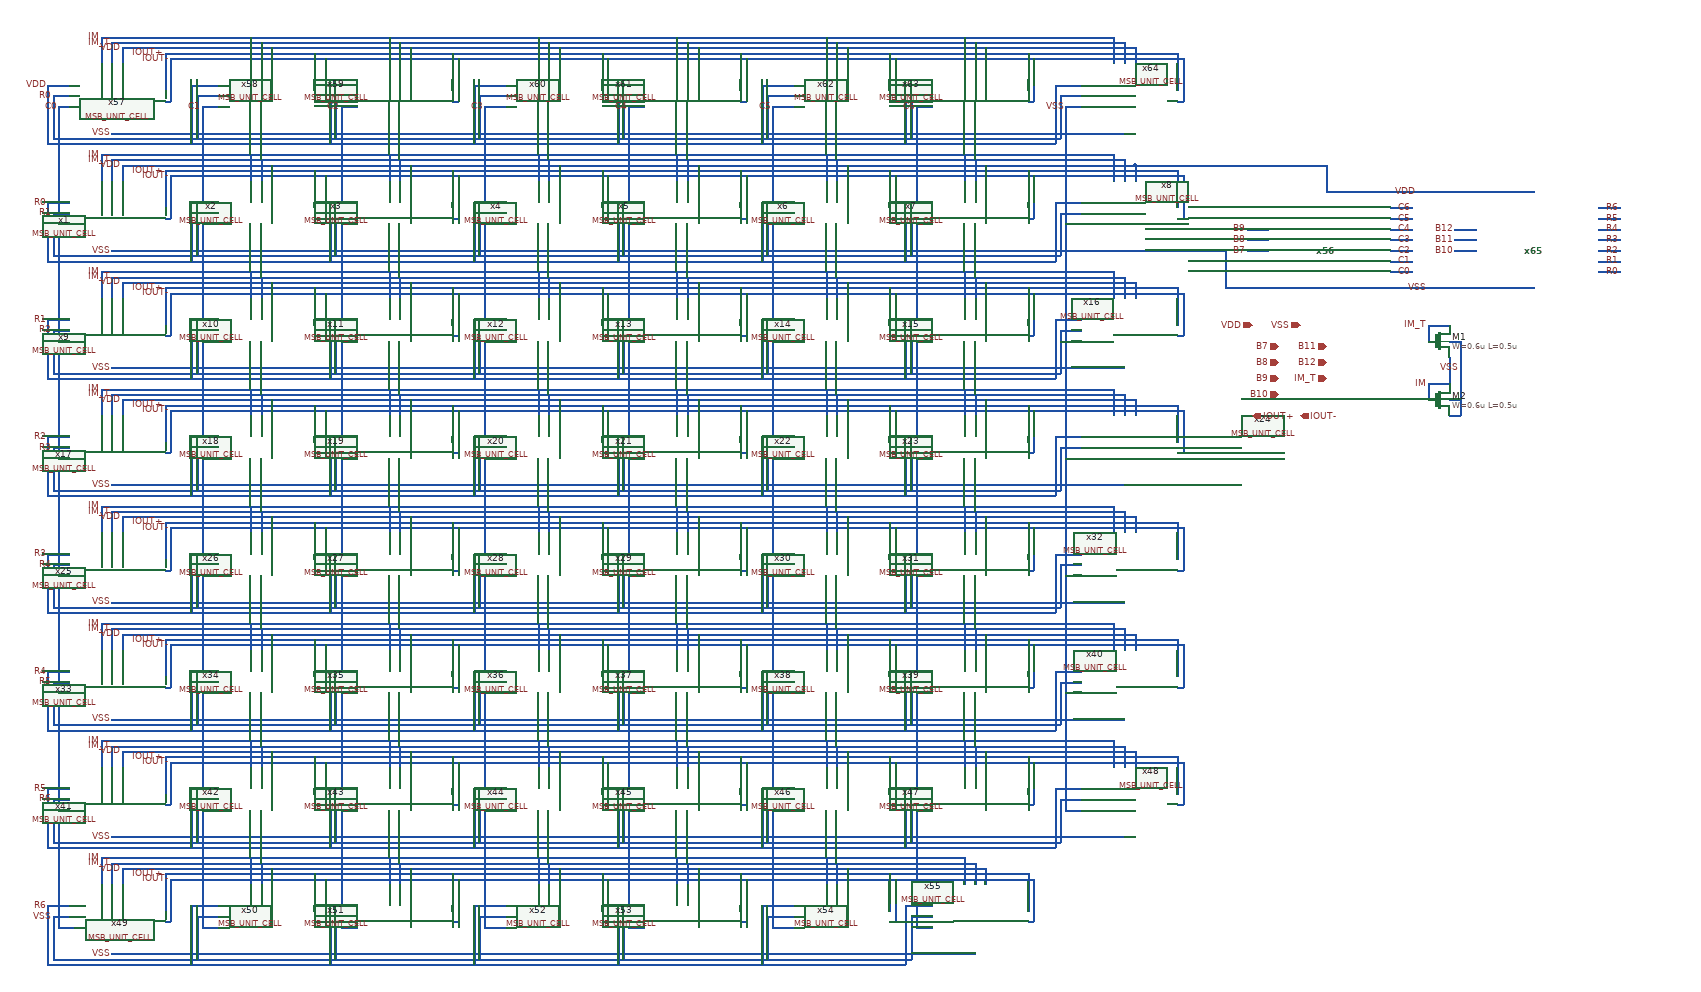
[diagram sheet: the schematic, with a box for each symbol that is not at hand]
v {xschem version=3.1.0 file_version=1.2
}
G {}
K {}
V {}
S {}
E {}
N 200 -1780 200 -1730 {
lab=IM}
N 200 -1780 2100 -1780 {
lab=IM}
N 2100 -1780 2100 -1730 {
lab=IM}
N 2120 -1770 2120 -1730 {
lab=IM_T}
N 2110 -1770 2120 -1770 {
lab=IM_T}
N 220 -1770 2110 -1770 {
lab=IM_T}
N 220 -1770 220 -1730 {
lab=IM_T}
N 240 -1760 240 -1730 {
lab=VDD}
N 240 -1760 2140 -1760 {
lab=VDD}
N 2140 -1760 2140 -1730 {
lab=VDD}
N 2220 -1750 2220 -1680 {
lab=IOUT+}
N 320 -1750 2220 -1750 {
lab=IOUT+}
N 320 -1750 320 -1680 {
lab=IOUT+}
N 320 -1660 330 -1660 {
lab=IOUT-}
N 330 -1740 330 -1660 {
lab=IOUT-}
N 330 -1740 2230 -1740 {
lab=IOUT-}
N 2230 -1740 2230 -1660 {
lab=IOUT-}
N 2220 -1660 2230 -1660 {
lab=IOUT-}
N 220 -1600 2120 -1600 {
lab=VSS}
N 480 -1780 480 -1730 {
lab=IM}
N 500 -1770 500 -1730 {
lab=IM_T}
N 520 -1760 520 -1730 {
lab=VDD}
N 600 -1750 600 -1680 {
lab=IOUT+}
N 600 -1660 620 -1660 {
lab=IOUT-}
N 620 -1740 620 -1660 {
lab=IOUT-}
N 740 -1780 740 -1730 {
lab=IM}
N 760 -1770 760 -1730 {
lab=IM_T}
N 780 -1760 780 -1730 {
lab=VDD}
N 860 -1750 860 -1680 {
lab=IOUT+}
N 870 -1740 870 -1660 {
lab=IOUT-}
N 860 -1660 870 -1660 {
lab=IOUT-}
N 1020 -1780 1020 -1730 {
lab=IM}
N 1040 -1770 1040 -1730 {
lab=IM_T}
N 1060 -1760 1060 -1730 {
lab=VDD}
N 1140 -1750 1140 -1680 {
lab=IOUT+}
N 1140 -1660 1150 -1660 {
lab=IOUT-}
N 1150 -1740 1150 -1660 {
lab=IOUT-}
N 1280 -1780 1280 -1730 {
lab=IM}
N 1300 -1770 1300 -1730 {
lab=IM_T}
N 1320 -1760 1320 -1730 {
lab=VDD}
N 1400 -1750 1400 -1680 {
lab=IOUT+}
N 1410 -1740 1410 -1660 {
lab=IOUT-}
N 1400 -1660 1410 -1660 {
lab=IOUT-}
N 1560 -1780 1560 -1730 {
lab=IM}
N 1580 -1770 1580 -1730 {
lab=IM_T}
N 1600 -1760 1600 -1730 {
lab=VDD}
N 1680 -1750 1680 -1680 {
lab=IOUT+}
N 1690 -1740 1690 -1660 {
lab=IOUT-}
N 1680 -1660 1690 -1660 {
lab=IOUT-}
N 1820 -1780 1820 -1730 {
lab=IM}
N 1840 -1770 1840 -1730 {
lab=IM_T}
N 1860 -1760 1860 -1730 {
lab=VDD}
N 1940 -1750 1940 -1680 {
lab=IOUT+}
N 1940 -1660 1950 -1660 {
lab=IOUT-}
N 1950 -1740 1950 -1660 {
lab=IOUT-}
N 110 -1670 140 -1670 {
lab=R0}
N 110 -1670 110 -1590 {
lab=R0}
N 110 -1590 2000 -1590 {
lab=R0}
N 2000 -1670 2000 -1590 {
lab=R0}
N 2000 -1670 2040 -1670 {
lab=R0}
N 1990 -1690 2040 -1690 {
lab=VDD}
N 1990 -1690 1990 -1580 {
lab=VDD}
N 100 -1580 1990 -1580 {
lab=VDD}
N 100 -1690 100 -1580 {
lab=VDD}
N 100 -1690 140 -1690 {
lab=VDD}
N 370 -1690 420 -1690 {
lab=VDD}
N 370 -1690 370 -1580 {
lab=VDD}
N 380 -1670 380 -1590 {
lab=R0}
N 380 -1670 420 -1670 {
lab=R0}
N 630 -1690 680 -1690 {
lab=VDD}
N 630 -1690 630 -1580 {
lab=VDD}
N 640 -1670 680 -1670 {
lab=R0}
N 640 -1670 640 -1590 {
lab=R0}
N 900 -1690 960 -1690 {
lab=VDD}
N 900 -1690 900 -1580 {
lab=VDD}
N 910 -1670 960 -1670 {
lab=R0}
N 910 -1670 910 -1590 {
lab=R0}
N 1170 -1690 1220 -1690 {
lab=VDD}
N 1170 -1690 1170 -1580 {
lab=VDD}
N 1180 -1670 1220 -1670 {
lab=R0}
N 1180 -1670 1180 -1590 {
lab=R0}
N 1440 -1690 1500 -1690 {
lab=VDD}
N 1440 -1690 1440 -1580 {
lab=VDD}
N 1450 -1670 1500 -1670 {
lab=R0}
N 1450 -1670 1450 -1590 {
lab=R0}
N 1710 -1690 1760 -1690 {
lab=VDD}
N 1710 -1690 1710 -1580 {
lab=VDD}
N 1720 -1670 1760 -1670 {
lab=R0}
N 1720 -1670 1720 -1590 {
lab=R0}
N 200 -1560 200 -1510 {
lab=IM}
N 200 -1560 2100 -1560 {
lab=IM}
N 2100 -1560 2100 -1510 {
lab=IM}
N 2120 -1550 2120 -1510 {
lab=IM_T}
N 2110 -1550 2120 -1550 {
lab=IM_T}
N 220 -1550 2110 -1550 {
lab=IM_T}
N 220 -1550 220 -1510 {
lab=IM_T}
N 240 -1540 240 -1510 {
lab=VDD}
N 240 -1540 2140 -1540 {
lab=VDD}
N 2140 -1540 2140 -1510 {
lab=VDD}
N 2220 -1530 2220 -1460 {
lab=IOUT+}
N 320 -1530 2220 -1530 {
lab=IOUT+}
N 320 -1530 320 -1460 {
lab=IOUT+}
N 320 -1440 330 -1440 {
lab=IOUT-}
N 330 -1520 330 -1440 {
lab=IOUT-}
N 330 -1520 2230 -1520 {
lab=IOUT-}
N 2230 -1520 2230 -1440 {
lab=IOUT-}
N 2220 -1440 2230 -1440 {
lab=IOUT-}
N 220 -1380 2120 -1380 {
lab=VSS}
N 480 -1560 480 -1510 {
lab=IM}
N 500 -1550 500 -1510 {
lab=IM_T}
N 520 -1540 520 -1510 {
lab=VDD}
N 600 -1530 600 -1460 {
lab=IOUT+}
N 600 -1440 620 -1440 {
lab=IOUT-}
N 620 -1520 620 -1440 {
lab=IOUT-}
N 740 -1560 740 -1510 {
lab=IM}
N 760 -1550 760 -1510 {
lab=IM_T}
N 780 -1540 780 -1510 {
lab=VDD}
N 860 -1530 860 -1460 {
lab=IOUT+}
N 870 -1520 870 -1440 {
lab=IOUT-}
N 860 -1440 870 -1440 {
lab=IOUT-}
N 1020 -1560 1020 -1510 {
lab=IM}
N 1040 -1550 1040 -1510 {
lab=IM_T}
N 1060 -1540 1060 -1510 {
lab=VDD}
N 1140 -1530 1140 -1460 {
lab=IOUT+}
N 1140 -1440 1150 -1440 {
lab=IOUT-}
N 1150 -1520 1150 -1440 {
lab=IOUT-}
N 1280 -1560 1280 -1510 {
lab=IM}
N 1300 -1550 1300 -1510 {
lab=IM_T}
N 1320 -1540 1320 -1510 {
lab=VDD}
N 1400 -1530 1400 -1460 {
lab=IOUT+}
N 1410 -1520 1410 -1440 {
lab=IOUT-}
N 1400 -1440 1410 -1440 {
lab=IOUT-}
N 1560 -1560 1560 -1510 {
lab=IM}
N 1580 -1550 1580 -1510 {
lab=IM_T}
N 1600 -1540 1600 -1510 {
lab=VDD}
N 1680 -1530 1680 -1460 {
lab=IOUT+}
N 1690 -1520 1690 -1440 {
lab=IOUT-}
N 1680 -1440 1690 -1440 {
lab=IOUT-}
N 1820 -1560 1820 -1510 {
lab=IM}
N 1840 -1550 1840 -1510 {
lab=IM_T}
N 1860 -1540 1860 -1510 {
lab=VDD}
N 1940 -1530 1940 -1460 {
lab=IOUT+}
N 1940 -1440 1950 -1440 {
lab=IOUT-}
N 1950 -1520 1950 -1440 {
lab=IOUT-}
N 110 -1450 140 -1450 {
lab=R1}
N 110 -1450 110 -1370 {
lab=R1}
N 110 -1370 2000 -1370 {
lab=R1}
N 2000 -1450 2000 -1370 {
lab=R1}
N 2000 -1450 2040 -1450 {
lab=R1}
N 1990 -1470 2040 -1470 {
lab=R0}
N 1990 -1470 1990 -1360 {
lab=R0}
N 100 -1360 1990 -1360 {
lab=R0}
N 100 -1470 100 -1360 {
lab=R0}
N 100 -1470 140 -1470 {
lab=R0}
N 370 -1470 420 -1470 {
lab=R0}
N 370 -1470 370 -1360 {
lab=R0}
N 380 -1450 380 -1370 {
lab=R1}
N 380 -1450 420 -1450 {
lab=R1}
N 630 -1470 680 -1470 {
lab=R0}
N 630 -1470 630 -1360 {
lab=R0}
N 640 -1450 680 -1450 {
lab=R1}
N 640 -1450 640 -1370 {
lab=R1}
N 900 -1470 960 -1470 {
lab=R0}
N 900 -1470 900 -1360 {
lab=R0}
N 910 -1450 960 -1450 {
lab=R1}
N 910 -1450 910 -1370 {
lab=R1}
N 1170 -1470 1220 -1470 {
lab=R0}
N 1170 -1470 1170 -1360 {
lab=R0}
N 1180 -1450 1220 -1450 {
lab=R1}
N 1180 -1450 1180 -1370 {
lab=R1}
N 1440 -1470 1500 -1470 {
lab=R0}
N 1440 -1470 1440 -1360 {
lab=R0}
N 1450 -1450 1500 -1450 {
lab=R1}
N 1450 -1450 1450 -1370 {
lab=R1}
N 1710 -1470 1760 -1470 {
lab=R0}
N 1710 -1470 1710 -1360 {
lab=R0}
N 1720 -1450 1760 -1450 {
lab=R1}
N 1720 -1450 1720 -1370 {
lab=R1}
N 200 -1340 200 -1290 {
lab=IM}
N 200 -1340 2100 -1340 {
lab=IM}
N 2100 -1340 2100 -1290 {
lab=IM}
N 2120 -1330 2120 -1290 {
lab=IM_T}
N 2110 -1330 2120 -1330 {
lab=IM_T}
N 220 -1330 2110 -1330 {
lab=IM_T}
N 220 -1330 220 -1290 {
lab=IM_T}
N 240 -1320 240 -1290 {
lab=VDD}
N 240 -1320 2140 -1320 {
lab=VDD}
N 2140 -1320 2140 -1290 {
lab=VDD}
N 2220 -1310 2220 -1240 {
lab=IOUT+}
N 320 -1310 2220 -1310 {
lab=IOUT+}
N 320 -1310 320 -1240 {
lab=IOUT+}
N 320 -1220 330 -1220 {
lab=IOUT-}
N 330 -1300 330 -1220 {
lab=IOUT-}
N 330 -1300 2230 -1300 {
lab=IOUT-}
N 2230 -1300 2230 -1220 {
lab=IOUT-}
N 2220 -1220 2230 -1220 {
lab=IOUT-}
N 220 -1160 2120 -1160 {
lab=VSS}
N 480 -1340 480 -1290 {
lab=IM}
N 500 -1330 500 -1290 {
lab=IM_T}
N 520 -1320 520 -1290 {
lab=VDD}
N 600 -1310 600 -1240 {
lab=IOUT+}
N 600 -1220 620 -1220 {
lab=IOUT-}
N 620 -1300 620 -1220 {
lab=IOUT-}
N 740 -1340 740 -1290 {
lab=IM}
N 760 -1330 760 -1290 {
lab=IM_T}
N 780 -1320 780 -1290 {
lab=VDD}
N 860 -1310 860 -1240 {
lab=IOUT+}
N 870 -1300 870 -1220 {
lab=IOUT-}
N 860 -1220 870 -1220 {
lab=IOUT-}
N 1020 -1340 1020 -1290 {
lab=IM}
N 1040 -1330 1040 -1290 {
lab=IM_T}
N 1060 -1320 1060 -1290 {
lab=VDD}
N 1140 -1310 1140 -1240 {
lab=IOUT+}
N 1140 -1220 1150 -1220 {
lab=IOUT-}
N 1150 -1300 1150 -1220 {
lab=IOUT-}
N 1280 -1340 1280 -1290 {
lab=IM}
N 1300 -1330 1300 -1290 {
lab=IM_T}
N 1320 -1320 1320 -1290 {
lab=VDD}
N 1400 -1310 1400 -1240 {
lab=IOUT+}
N 1410 -1300 1410 -1220 {
lab=IOUT-}
N 1400 -1220 1410 -1220 {
lab=IOUT-}
N 1560 -1340 1560 -1290 {
lab=IM}
N 1580 -1330 1580 -1290 {
lab=IM_T}
N 1600 -1320 1600 -1290 {
lab=VDD}
N 1680 -1310 1680 -1240 {
lab=IOUT+}
N 1690 -1300 1690 -1220 {
lab=IOUT-}
N 1680 -1220 1690 -1220 {
lab=IOUT-}
N 1820 -1340 1820 -1290 {
lab=IM}
N 1840 -1330 1840 -1290 {
lab=IM_T}
N 1860 -1320 1860 -1290 {
lab=VDD}
N 1940 -1310 1940 -1240 {
lab=IOUT+}
N 1940 -1220 1950 -1220 {
lab=IOUT-}
N 1950 -1300 1950 -1220 {
lab=IOUT-}
N 110 -1230 140 -1230 {
lab=R2}
N 110 -1230 110 -1150 {
lab=R2}
N 110 -1150 2000 -1150 {
lab=R2}
N 2000 -1230 2000 -1150 {
lab=R2}
N 2000 -1230 2040 -1230 {
lab=R2}
N 1990 -1250 2040 -1250 {
lab=R1}
N 1990 -1250 1990 -1140 {
lab=R1}
N 100 -1140 1990 -1140 {
lab=R1}
N 100 -1250 100 -1140 {
lab=R1}
N 100 -1250 140 -1250 {
lab=R1}
N 370 -1250 420 -1250 {
lab=R1}
N 370 -1250 370 -1140 {
lab=R1}
N 380 -1230 380 -1150 {
lab=R2}
N 380 -1230 420 -1230 {
lab=R2}
N 630 -1250 680 -1250 {
lab=R1}
N 630 -1250 630 -1140 {
lab=R1}
N 640 -1230 680 -1230 {
lab=R2}
N 640 -1230 640 -1150 {
lab=R2}
N 900 -1250 960 -1250 {
lab=R1}
N 900 -1250 900 -1140 {
lab=R1}
N 910 -1230 960 -1230 {
lab=R2}
N 910 -1230 910 -1150 {
lab=R2}
N 1170 -1250 1220 -1250 {
lab=R1}
N 1170 -1250 1170 -1140 {
lab=R1}
N 1180 -1230 1220 -1230 {
lab=R2}
N 1180 -1230 1180 -1150 {
lab=R2}
N 1440 -1250 1500 -1250 {
lab=R1}
N 1440 -1250 1440 -1140 {
lab=R1}
N 1450 -1230 1500 -1230 {
lab=R2}
N 1450 -1230 1450 -1150 {
lab=R2}
N 1710 -1250 1760 -1250 {
lab=R1}
N 1710 -1250 1710 -1140 {
lab=R1}
N 1720 -1230 1760 -1230 {
lab=R2}
N 1720 -1230 1720 -1150 {
lab=R2}
N 200 -1120 200 -1070 {
lab=IM}
N 200 -1120 2100 -1120 {
lab=IM}
N 2100 -1120 2100 -1070 {
lab=IM}
N 2120 -1110 2120 -1070 {
lab=IM_T}
N 2110 -1110 2120 -1110 {
lab=IM_T}
N 220 -1110 2110 -1110 {
lab=IM_T}
N 220 -1110 220 -1070 {
lab=IM_T}
N 240 -1100 240 -1070 {
lab=VDD}
N 240 -1100 2140 -1100 {
lab=VDD}
N 2140 -1100 2140 -1070 {
lab=VDD}
N 2220 -1090 2220 -1020 {
lab=IOUT+}
N 320 -1090 2220 -1090 {
lab=IOUT+}
N 320 -1090 320 -1020 {
lab=IOUT+}
N 320 -1000 330 -1000 {
lab=IOUT-}
N 330 -1080 330 -1000 {
lab=IOUT-}
N 330 -1080 2230 -1080 {
lab=IOUT-}
N 2230 -1080 2230 -1000 {
lab=IOUT-}
N 2220 -1000 2230 -1000 {
lab=IOUT-}
N 220 -940 2120 -940 {
lab=VSS}
N 480 -1120 480 -1070 {
lab=IM}
N 500 -1110 500 -1070 {
lab=IM_T}
N 520 -1100 520 -1070 {
lab=VDD}
N 600 -1090 600 -1020 {
lab=IOUT+}
N 600 -1000 620 -1000 {
lab=IOUT-}
N 620 -1080 620 -1000 {
lab=IOUT-}
N 740 -1120 740 -1070 {
lab=IM}
N 760 -1110 760 -1070 {
lab=IM_T}
N 780 -1100 780 -1070 {
lab=VDD}
N 860 -1090 860 -1020 {
lab=IOUT+}
N 870 -1080 870 -1000 {
lab=IOUT-}
N 860 -1000 870 -1000 {
lab=IOUT-}
N 1020 -1120 1020 -1070 {
lab=IM}
N 1040 -1110 1040 -1070 {
lab=IM_T}
N 1060 -1100 1060 -1070 {
lab=VDD}
N 1140 -1090 1140 -1020 {
lab=IOUT+}
N 1140 -1000 1150 -1000 {
lab=IOUT-}
N 1150 -1080 1150 -1000 {
lab=IOUT-}
N 1280 -1120 1280 -1070 {
lab=IM}
N 1300 -1110 1300 -1070 {
lab=IM_T}
N 1320 -1100 1320 -1070 {
lab=VDD}
N 1400 -1090 1400 -1020 {
lab=IOUT+}
N 1410 -1080 1410 -1000 {
lab=IOUT-}
N 1400 -1000 1410 -1000 {
lab=IOUT-}
N 1560 -1120 1560 -1070 {
lab=IM}
N 1580 -1110 1580 -1070 {
lab=IM_T}
N 1600 -1100 1600 -1070 {
lab=VDD}
N 1680 -1090 1680 -1020 {
lab=IOUT+}
N 1690 -1080 1690 -1000 {
lab=IOUT-}
N 1680 -1000 1690 -1000 {
lab=IOUT-}
N 1820 -1120 1820 -1070 {
lab=IM}
N 1840 -1110 1840 -1070 {
lab=IM_T}
N 1860 -1100 1860 -1070 {
lab=VDD}
N 1940 -1090 1940 -1020 {
lab=IOUT+}
N 1940 -1000 1950 -1000 {
lab=IOUT-}
N 1950 -1080 1950 -1000 {
lab=IOUT-}
N 110 -1010 140 -1010 {
lab=R3}
N 110 -1010 110 -930 {
lab=R3}
N 110 -930 2000 -930 {
lab=R3}
N 2000 -1010 2000 -930 {
lab=R3}
N 2000 -1010 2040 -1010 {
lab=R3}
N 1990 -1030 2040 -1030 {
lab=R2}
N 1990 -1030 1990 -920 {
lab=R2}
N 100 -920 1990 -920 {
lab=R2}
N 100 -1030 100 -920 {
lab=R2}
N 100 -1030 140 -1030 {
lab=R2}
N 370 -1030 420 -1030 {
lab=R2}
N 370 -1030 370 -920 {
lab=R2}
N 380 -1010 380 -930 {
lab=R3}
N 380 -1010 420 -1010 {
lab=R3}
N 630 -1030 680 -1030 {
lab=R2}
N 630 -1030 630 -920 {
lab=R2}
N 640 -1010 680 -1010 {
lab=R3}
N 640 -1010 640 -930 {
lab=R3}
N 900 -1030 960 -1030 {
lab=R2}
N 900 -1030 900 -920 {
lab=R2}
N 910 -1010 960 -1010 {
lab=R3}
N 910 -1010 910 -930 {
lab=R3}
N 1170 -1030 1220 -1030 {
lab=R2}
N 1170 -1030 1170 -920 {
lab=R2}
N 1180 -1010 1220 -1010 {
lab=R3}
N 1180 -1010 1180 -930 {
lab=R3}
N 1440 -1030 1500 -1030 {
lab=R2}
N 1440 -1030 1440 -920 {
lab=R2}
N 1450 -1010 1500 -1010 {
lab=R3}
N 1450 -1010 1450 -930 {
lab=R3}
N 1710 -1030 1760 -1030 {
lab=R2}
N 1710 -1030 1710 -920 {
lab=R2}
N 1720 -1010 1760 -1010 {
lab=R3}
N 1720 -1010 1720 -930 {
lab=R3}
N 200 -900 200 -850 {
lab=IM}
N 200 -900 2100 -900 {
lab=IM}
N 2100 -900 2100 -850 {
lab=IM}
N 2120 -890 2120 -850 {
lab=IM_T}
N 2110 -890 2120 -890 {
lab=IM_T}
N 220 -890 2110 -890 {
lab=IM_T}
N 220 -890 220 -850 {
lab=IM_T}
N 240 -880 240 -850 {
lab=VDD}
N 240 -880 2140 -880 {
lab=VDD}
N 2140 -880 2140 -850 {
lab=VDD}
N 2220 -870 2220 -800 {
lab=IOUT+}
N 320 -870 2220 -870 {
lab=IOUT+}
N 320 -870 320 -800 {
lab=IOUT+}
N 320 -780 330 -780 {
lab=IOUT-}
N 330 -860 330 -780 {
lab=IOUT-}
N 330 -860 2230 -860 {
lab=IOUT-}
N 2230 -860 2230 -780 {
lab=IOUT-}
N 2220 -780 2230 -780 {
lab=IOUT-}
N 220 -720 2120 -720 {
lab=VSS}
N 480 -900 480 -850 {
lab=IM}
N 500 -890 500 -850 {
lab=IM_T}
N 520 -880 520 -850 {
lab=VDD}
N 600 -870 600 -800 {
lab=IOUT+}
N 600 -780 620 -780 {
lab=IOUT-}
N 620 -860 620 -780 {
lab=IOUT-}
N 740 -900 740 -850 {
lab=IM}
N 760 -890 760 -850 {
lab=IM_T}
N 780 -880 780 -850 {
lab=VDD}
N 860 -870 860 -800 {
lab=IOUT+}
N 870 -860 870 -780 {
lab=IOUT-}
N 860 -780 870 -780 {
lab=IOUT-}
N 1020 -900 1020 -850 {
lab=IM}
N 1040 -890 1040 -850 {
lab=IM_T}
N 1060 -880 1060 -850 {
lab=VDD}
N 1140 -870 1140 -800 {
lab=IOUT+}
N 1140 -780 1150 -780 {
lab=IOUT-}
N 1150 -860 1150 -780 {
lab=IOUT-}
N 1280 -900 1280 -850 {
lab=IM}
N 1300 -890 1300 -850 {
lab=IM_T}
N 1320 -880 1320 -850 {
lab=VDD}
N 1400 -870 1400 -800 {
lab=IOUT+}
N 1410 -860 1410 -780 {
lab=IOUT-}
N 1400 -780 1410 -780 {
lab=IOUT-}
N 1560 -900 1560 -850 {
lab=IM}
N 1580 -890 1580 -850 {
lab=IM_T}
N 1600 -880 1600 -850 {
lab=VDD}
N 1680 -870 1680 -800 {
lab=IOUT+}
N 1690 -860 1690 -780 {
lab=IOUT-}
N 1680 -780 1690 -780 {
lab=IOUT-}
N 1820 -900 1820 -850 {
lab=IM}
N 1840 -890 1840 -850 {
lab=IM_T}
N 1860 -880 1860 -850 {
lab=VDD}
N 1940 -870 1940 -800 {
lab=IOUT+}
N 1940 -780 1950 -780 {
lab=IOUT-}
N 1950 -860 1950 -780 {
lab=IOUT-}
N 110 -790 140 -790 {
lab=R4}
N 110 -790 110 -710 {
lab=R4}
N 110 -710 2000 -710 {
lab=R4}
N 2000 -790 2000 -710 {
lab=R4}
N 2000 -790 2040 -790 {
lab=R4}
N 1990 -810 2040 -810 {
lab=R3}
N 1990 -810 1990 -700 {
lab=R3}
N 100 -700 1990 -700 {
lab=R3}
N 100 -810 100 -700 {
lab=R3}
N 100 -810 140 -810 {
lab=R3}
N 370 -810 420 -810 {
lab=R3}
N 370 -810 370 -700 {
lab=R3}
N 380 -790 380 -710 {
lab=R4}
N 380 -790 420 -790 {
lab=R4}
N 630 -810 680 -810 {
lab=R3}
N 630 -810 630 -700 {
lab=R3}
N 640 -790 680 -790 {
lab=R4}
N 640 -790 640 -710 {
lab=R4}
N 900 -810 960 -810 {
lab=R3}
N 900 -810 900 -700 {
lab=R3}
N 910 -790 960 -790 {
lab=R4}
N 910 -790 910 -710 {
lab=R4}
N 1170 -810 1220 -810 {
lab=R3}
N 1170 -810 1170 -700 {
lab=R3}
N 1180 -790 1220 -790 {
lab=R4}
N 1180 -790 1180 -710 {
lab=R4}
N 1440 -810 1500 -810 {
lab=R3}
N 1440 -810 1440 -700 {
lab=R3}
N 1450 -790 1500 -790 {
lab=R4}
N 1450 -790 1450 -710 {
lab=R4}
N 1710 -810 1760 -810 {
lab=R3}
N 1710 -810 1710 -700 {
lab=R3}
N 1720 -790 1760 -790 {
lab=R4}
N 1720 -790 1720 -710 {
lab=R4}
N 200 -680 200 -630 {
lab=IM}
N 200 -680 2100 -680 {
lab=IM}
N 2100 -680 2100 -630 {
lab=IM}
N 2120 -670 2120 -630 {
lab=IM_T}
N 2110 -670 2120 -670 {
lab=IM_T}
N 220 -670 2110 -670 {
lab=IM_T}
N 220 -670 220 -630 {
lab=IM_T}
N 240 -660 240 -630 {
lab=VDD}
N 240 -660 2140 -660 {
lab=VDD}
N 2140 -660 2140 -630 {
lab=VDD}
N 2220 -650 2220 -580 {
lab=IOUT+}
N 320 -650 2220 -650 {
lab=IOUT+}
N 320 -650 320 -580 {
lab=IOUT+}
N 320 -560 330 -560 {
lab=IOUT-}
N 330 -640 330 -560 {
lab=IOUT-}
N 330 -640 2230 -640 {
lab=IOUT-}
N 2230 -640 2230 -560 {
lab=IOUT-}
N 2220 -560 2230 -560 {
lab=IOUT-}
N 220 -500 2120 -500 {
lab=VSS}
N 480 -680 480 -630 {
lab=IM}
N 500 -670 500 -630 {
lab=IM_T}
N 520 -660 520 -630 {
lab=VDD}
N 600 -650 600 -580 {
lab=IOUT+}
N 600 -560 620 -560 {
lab=IOUT-}
N 620 -640 620 -560 {
lab=IOUT-}
N 740 -680 740 -630 {
lab=IM}
N 760 -670 760 -630 {
lab=IM_T}
N 780 -660 780 -630 {
lab=VDD}
N 860 -650 860 -580 {
lab=IOUT+}
N 870 -640 870 -560 {
lab=IOUT-}
N 860 -560 870 -560 {
lab=IOUT-}
N 1020 -680 1020 -630 {
lab=IM}
N 1040 -670 1040 -630 {
lab=IM_T}
N 1060 -660 1060 -630 {
lab=VDD}
N 1140 -650 1140 -580 {
lab=IOUT+}
N 1140 -560 1150 -560 {
lab=IOUT-}
N 1150 -640 1150 -560 {
lab=IOUT-}
N 1280 -680 1280 -630 {
lab=IM}
N 1300 -670 1300 -630 {
lab=IM_T}
N 1320 -660 1320 -630 {
lab=VDD}
N 1400 -650 1400 -580 {
lab=IOUT+}
N 1410 -640 1410 -560 {
lab=IOUT-}
N 1400 -560 1410 -560 {
lab=IOUT-}
N 1560 -680 1560 -630 {
lab=IM}
N 1580 -670 1580 -630 {
lab=IM_T}
N 1600 -660 1600 -630 {
lab=VDD}
N 1680 -650 1680 -580 {
lab=IOUT+}
N 1690 -640 1690 -560 {
lab=IOUT-}
N 1680 -560 1690 -560 {
lab=IOUT-}
N 1820 -680 1820 -630 {
lab=IM}
N 1840 -670 1840 -630 {
lab=IM_T}
N 1860 -660 1860 -630 {
lab=VDD}
N 1940 -650 1940 -580 {
lab=IOUT+}
N 1940 -560 1950 -560 {
lab=IOUT-}
N 1950 -640 1950 -560 {
lab=IOUT-}
N 110 -570 140 -570 {
lab=R5}
N 110 -570 110 -490 {
lab=R5}
N 110 -490 2000 -490 {
lab=R5}
N 2000 -570 2000 -490 {
lab=R5}
N 2000 -570 2040 -570 {
lab=R5}
N 1990 -590 2040 -590 {
lab=R4}
N 1990 -590 1990 -480 {
lab=R4}
N 100 -480 1990 -480 {
lab=R4}
N 100 -590 100 -480 {
lab=R4}
N 100 -590 140 -590 {
lab=R4}
N 370 -590 420 -590 {
lab=R4}
N 370 -590 370 -480 {
lab=R4}
N 380 -570 380 -490 {
lab=R5}
N 380 -570 420 -570 {
lab=R5}
N 630 -590 680 -590 {
lab=R4}
N 630 -590 630 -480 {
lab=R4}
N 640 -570 680 -570 {
lab=R5}
N 640 -570 640 -490 {
lab=R5}
N 900 -590 960 -590 {
lab=R4}
N 900 -590 900 -480 {
lab=R4}
N 910 -570 960 -570 {
lab=R5}
N 910 -570 910 -490 {
lab=R5}
N 1170 -590 1220 -590 {
lab=R4}
N 1170 -590 1170 -480 {
lab=R4}
N 1180 -570 1220 -570 {
lab=R5}
N 1180 -570 1180 -490 {
lab=R5}
N 1440 -590 1500 -590 {
lab=R4}
N 1440 -590 1440 -480 {
lab=R4}
N 1450 -570 1500 -570 {
lab=R5}
N 1450 -570 1450 -490 {
lab=R5}
N 1710 -590 1760 -590 {
lab=R4}
N 1710 -590 1710 -480 {
lab=R4}
N 1720 -570 1760 -570 {
lab=R5}
N 1720 -570 1720 -490 {
lab=R5}
N 200 -460 200 -410 {
lab=IM}
N 200 -460 2100 -460 {
lab=IM}
N 2100 -460 2100 -410 {
lab=IM}
N 2120 -450 2120 -410 {
lab=IM_T}
N 2110 -450 2120 -450 {
lab=IM_T}
N 220 -450 2110 -450 {
lab=IM_T}
N 220 -450 220 -410 {
lab=IM_T}
N 240 -440 240 -410 {
lab=VDD}
N 240 -440 2140 -440 {
lab=VDD}
N 2140 -440 2140 -410 {
lab=VDD}
N 2220 -430 2220 -360 {
lab=IOUT+}
N 320 -430 2220 -430 {
lab=IOUT+}
N 320 -430 320 -360 {
lab=IOUT+}
N 320 -340 330 -340 {
lab=IOUT-}
N 330 -420 330 -340 {
lab=IOUT-}
N 330 -420 2230 -420 {
lab=IOUT-}
N 2230 -420 2230 -340 {
lab=IOUT-}
N 2220 -340 2230 -340 {
lab=IOUT-}
N 220 -280 2120 -280 {
lab=VSS}
N 480 -460 480 -410 {
lab=IM}
N 500 -450 500 -410 {
lab=IM_T}
N 520 -440 520 -410 {
lab=VDD}
N 600 -430 600 -360 {
lab=IOUT+}
N 600 -340 620 -340 {
lab=IOUT-}
N 620 -420 620 -340 {
lab=IOUT-}
N 740 -460 740 -410 {
lab=IM}
N 760 -450 760 -410 {
lab=IM_T}
N 780 -440 780 -410 {
lab=VDD}
N 860 -430 860 -360 {
lab=IOUT+}
N 870 -420 870 -340 {
lab=IOUT-}
N 860 -340 870 -340 {
lab=IOUT-}
N 1020 -460 1020 -410 {
lab=IM}
N 1040 -450 1040 -410 {
lab=IM_T}
N 1060 -440 1060 -410 {
lab=VDD}
N 1140 -430 1140 -360 {
lab=IOUT+}
N 1140 -340 1150 -340 {
lab=IOUT-}
N 1150 -420 1150 -340 {
lab=IOUT-}
N 1280 -460 1280 -410 {
lab=IM}
N 1300 -450 1300 -410 {
lab=IM_T}
N 1320 -440 1320 -410 {
lab=VDD}
N 1400 -430 1400 -360 {
lab=IOUT+}
N 1410 -420 1410 -340 {
lab=IOUT-}
N 1400 -340 1410 -340 {
lab=IOUT-}
N 1560 -460 1560 -410 {
lab=IM}
N 1580 -450 1580 -410 {
lab=IM_T}
N 1600 -440 1600 -410 {
lab=VDD}
N 1680 -430 1680 -360 {
lab=IOUT+}
N 1690 -420 1690 -340 {
lab=IOUT-}
N 1680 -340 1690 -340 {
lab=IOUT-}
N 1820 -460 1820 -410 {
lab=IM}
N 1840 -450 1840 -410 {
lab=IM_T}
N 1860 -440 1860 -410 {
lab=VDD}
N 1940 -430 1940 -360 {
lab=IOUT+}
N 1940 -340 1950 -340 {
lab=IOUT-}
N 1950 -420 1950 -340 {
lab=IOUT-}
N 110 -350 140 -350 {
lab=R6}
N 110 -350 110 -270 {
lab=R6}
N 110 -270 2000 -270 {
lab=R6}
N 2000 -350 2000 -270 {
lab=R6}
N 2000 -350 2040 -350 {
lab=R6}
N 1990 -370 2040 -370 {
lab=R5}
N 1990 -370 1990 -260 {
lab=R5}
N 100 -260 1990 -260 {
lab=R5}
N 100 -370 100 -260 {
lab=R5}
N 100 -370 140 -370 {
lab=R5}
N 370 -370 420 -370 {
lab=R5}
N 370 -370 370 -260 {
lab=R5}
N 380 -350 380 -270 {
lab=R6}
N 380 -350 420 -350 {
lab=R6}
N 630 -370 680 -370 {
lab=R5}
N 630 -370 630 -260 {
lab=R5}
N 640 -350 680 -350 {
lab=R6}
N 640 -350 640 -270 {
lab=R6}
N 900 -370 960 -370 {
lab=R5}
N 900 -370 900 -260 {
lab=R5}
N 910 -350 960 -350 {
lab=R6}
N 910 -350 910 -270 {
lab=R6}
N 1170 -370 1220 -370 {
lab=R5}
N 1170 -370 1170 -260 {
lab=R5}
N 1180 -350 1220 -350 {
lab=R6}
N 1180 -350 1180 -270 {
lab=R6}
N 1440 -370 1500 -370 {
lab=R5}
N 1440 -370 1440 -260 {
lab=R5}
N 1450 -350 1500 -350 {
lab=R6}
N 1450 -350 1450 -270 {
lab=R6}
N 1710 -370 1760 -370 {
lab=R5}
N 1710 -370 1710 -260 {
lab=R5}
N 1720 -350 1760 -350 {
lab=R6}
N 1720 -350 1720 -270 {
lab=R6}
N 200 -240 200 -190 {
lab=IM}
N 220 -230 220 -190 {
lab=IM_T}
N 240 -220 240 -190 {
lab=VDD}
N 320 -210 320 -140 {
lab=IOUT+}
N 320 -120 330 -120 {
lab=IOUT-}
N 330 -200 330 -120 {
lab=IOUT-}
N 480 -240 480 -190 {
lab=IM}
N 500 -230 500 -190 {
lab=IM_T}
N 520 -220 520 -190 {
lab=VDD}
N 600 -210 600 -140 {
lab=IOUT+}
N 600 -120 620 -120 {
lab=IOUT-}
N 620 -200 620 -120 {
lab=IOUT-}
N 740 -240 740 -190 {
lab=IM}
N 760 -230 760 -190 {
lab=IM_T}
N 780 -220 780 -190 {
lab=VDD}
N 860 -210 860 -140 {
lab=IOUT+}
N 870 -200 870 -120 {
lab=IOUT-}
N 860 -120 870 -120 {
lab=IOUT-}
N 1020 -240 1020 -190 {
lab=IM}
N 1040 -230 1040 -190 {
lab=IM_T}
N 1060 -220 1060 -190 {
lab=VDD}
N 1140 -210 1140 -140 {
lab=IOUT+}
N 1140 -120 1150 -120 {
lab=IOUT-}
N 1150 -200 1150 -120 {
lab=IOUT-}
N 1280 -240 1280 -190 {
lab=IM}
N 1300 -230 1300 -190 {
lab=IM_T}
N 1320 -220 1320 -190 {
lab=VDD}
N 1400 -210 1400 -140 {
lab=IOUT+}
N 1410 -200 1410 -120 {
lab=IOUT-}
N 1400 -120 1410 -120 {
lab=IOUT-}
N 1560 -240 1560 -190 {
lab=IM}
N 1580 -230 1580 -190 {
lab=IM_T}
N 1600 -220 1600 -190 {
lab=VDD}
N 1680 -210 1680 -140 {
lab=IOUT+}
N 1690 -200 1690 -120 {
lab=IOUT-}
N 1680 -120 1690 -120 {
lab=IOUT-}
N 1820 -240 1820 -190 {
lab=IM}
N 1840 -230 1840 -190 {
lab=IM_T}
N 1860 -220 1860 -190 {
lab=VDD}
N 1940 -210 1940 -140 {
lab=IOUT+}
N 1940 -120 1950 -120 {
lab=IOUT-}
N 1950 -200 1950 -120 {
lab=IOUT-}
N 110 -130 140 -130 {
lab=VSS}
N 110 -130 110 -50 {
lab=VSS}
N 100 -150 100 -40 {
lab=R6}
N 100 -150 140 -150 {
lab=R6}
N 370 -150 420 -150 {
lab=R6}
N 370 -150 370 -40 {
lab=R6}
N 380 -130 380 -50 {
lab=VSS}
N 380 -130 420 -130 {
lab=VSS}
N 630 -150 680 -150 {
lab=R6}
N 630 -150 630 -40 {
lab=R6}
N 640 -130 680 -130 {
lab=VSS}
N 640 -130 640 -50 {
lab=VSS}
N 900 -150 960 -150 {
lab=R6}
N 900 -150 900 -40 {
lab=R6}
N 910 -130 960 -130 {
lab=VSS}
N 910 -130 910 -50 {
lab=VSS}
N 1170 -150 1220 -150 {
lab=R6}
N 1170 -150 1170 -40 {
lab=R6}
N 1180 -130 1220 -130 {
lab=VSS}
N 1180 -130 1180 -50 {
lab=VSS}
N 1440 -150 1500 -150 {
lab=R6}
N 1440 -150 1440 -40 {
lab=R6}
N 1450 -130 1500 -130 {
lab=VSS}
N 1450 -130 1450 -50 {
lab=VSS}
N 1710 -150 1760 -150 {
lab=R6}
N 1710 -150 1710 -40 {
lab=R6}
N 1720 -130 1760 -130 {
lab=VSS}
N 1720 -130 1720 -50 {
lab=VSS}
N 120 -1650 140 -1650 {
lab=C0}
N 120 -1650 120 -110 {
lab=C0}
N 120 -110 150 -110 {
lab=C0}
N 120 -330 140 -330 {
lab=C0}
N 120 -550 140 -550 {
lab=C0}
N 120 -770 140 -770 {
lab=C0}
N 120 -990 140 -990 {
lab=C0}
N 120 -1210 140 -1210 {
lab=C0}
N 120 -1430 140 -1430 {
lab=C0}
N 390 -1650 420 -1650 {
lab=C1}
N 390 -1650 390 -110 {
lab=C1}
N 390 -110 420 -110 {
lab=C1}
N 650 -110 680 -110 {
lab=C2}
N 650 -1650 650 -110 {
lab=C2}
N 650 -1650 680 -1650 {
lab=C2}
N 920 -1650 960 -1650 {
lab=C3}
N 920 -1650 920 -110 {
lab=C3}
N 920 -110 960 -110 {
lab=C3}
N 1190 -110 1220 -110 {
lab=C4}
N 1190 -1650 1190 -110 {
lab=C4}
N 1190 -1650 1220 -1650 {
lab=C4}
N 1460 -1650 1500 -1650 {
lab=C5}
N 1460 -1650 1460 -110 {
lab=C5}
N 1460 -110 1500 -110 {
lab=C5}
N 1730 -110 1760 -110 {
lab=C6}
N 1730 -1650 1730 -110 {
lab=C6}
N 1730 -1650 1760 -1650 {
lab=C6}
N 2010 -1650 2040 -1650 {
lab=VSS}
N 2010 -330 2040 -330 {
lab=VSS}
N 2010 -550 2040 -550 {
lab=VSS}
N 1730 -550 1760 -550 {
lab=C6}
N 1730 -330 1760 -330 {
lab=C6}
N 1460 -330 1500 -330 {
lab=C5}
N 2010 -1430 2040 -1430 {
lab=VSS}
N 1730 -1430 1760 -1430 {
lab=C6}
N 1460 -1430 1500 -1430 {
lab=C5}
N 1190 -1430 1220 -1430 {
lab=C4}
N 920 -1430 960 -1430 {
lab=C3}
N 650 -1430 680 -1430 {
lab=C2}
N 390 -1430 420 -1430 {
lab=C1}
N 390 -1210 420 -1210 {
lab=C1}
N 650 -1210 680 -1210 {
lab=C2}
N 920 -1210 960 -1210 {
lab=C3}
N 1460 -1210 1500 -1210 {
lab=C5}
N 1190 -1210 1220 -1210 {
lab=C4}
N 1730 -1210 1760 -1210 {
lab=C6}
N 2000 -1210 2040 -1210 {
lab=R2}
N 2010 -990 2040 -990 {
lab=VSS}
N 1730 -990 1760 -990 {
lab=C6}
N 1460 -990 1500 -990 {
lab=C5}
N 1190 -990 1220 -990 {
lab=C4}
N 920 -990 960 -990 {
lab=C3}
N 650 -990 680 -990 {
lab=C2}
N 390 -990 420 -990 {
lab=C1}
N 390 -770 420 -770 {
lab=C1}
N 650 -770 680 -770 {
lab=C2}
N 920 -770 960 -770 {
lab=C3}
N 1190 -770 1220 -770 {
lab=C4}
N 1460 -770 1500 -770 {
lab=C5}
N 1730 -770 1760 -770 {
lab=C6}
N 2010 -770 2040 -770 {
lab=VSS}
N 1460 -550 1500 -550 {
lab=C5}
N 1190 -550 1220 -550 {
lab=C4}
N 920 -550 960 -550 {
lab=C3}
N 650 -550 680 -550 {
lab=C2}
N 390 -550 420 -550 {
lab=C1}
N 390 -330 420 -330 {
lab=C1}
N 670 -330 680 -330 {
lab=C2}
N 650 -330 670 -330 {
lab=C2}
N 920 -330 960 -330 {
lab=C3}
N 1190 -330 1220 -330 {
lab=C4}
N 220 -60 1840 -60 {
lab=VSS}
N 110 -50 1720 -50 {
lab=VSS}
N 100 -40 1710 -40 {
lab=R6}
N 200 -240 1820 -240 {
lab=IM}
N 220 -230 1840 -230 {
lab=IM_T}
N 240 -220 1860 -220 {
lab=VDD}
N 320 -210 1940 -210 {
lab=IOUT+}
N 330 -200 1950 -200 {
lab=IOUT-}
N 2010 -1650 2010 -330 {
lab=VSS}
N 2140 -1540 2500 -1540 {
lab=VDD}
N 2500 -1540 2500 -1490 {
lab=VDD}
N 2500 -1490 2890 -1490 {
lab=VDD}
N 2500 -1310 2890 -1310 {
lab=VSS}
N 2310 -1310 2500 -1310 {
lab=VSS}
N 2310 -1380 2310 -1310 {
lab=VSS}
N 2120 -1380 2310 -1380 {
lab=VSS}
N 2350 -1420 2390 -1420 {
lab=B9}
N 2350 -1400 2390 -1400 {
lab=B8}
N 2350 -1380 2390 -1380 {
lab=B7}
N 2740 -1420 2780 -1420 {
lab=B12}
N 2740 -1400 2780 -1400 {
lab=B11}
N 2740 -1380 2780 -1380 {
lab=B10}
N 2620 -1460 2660 -1460 {
lab=C6}
N 2620 -1440 2660 -1440 {
lab=C5}
N 2620 -1420 2630 -1420 {
lab=C4}
N 2630 -1420 2660 -1420 {
lab=C4}
N 2620 -1400 2660 -1400 {
lab=C3}
N 2620 -1380 2660 -1380 {
lab=C2}
N 2620 -1340 2660 -1340 {
lab=C0}
N 3010 -1460 3050 -1460 {
lab=R6}
N 3010 -1440 3050 -1440 {
lab=R5}
N 3010 -1420 3020 -1420 {
lab=R4}
N 3020 -1420 3050 -1420 {
lab=R4}
N 3010 -1400 3050 -1400 {
lab=R3}
N 3010 -1380 3050 -1380 {
lab=R2}
N 3010 -1360 3050 -1360 {
lab=R1}
N 3010 -1340 3050 -1340 {
lab=R0}
N 2690 -1240 2730 -1240 {
lab=IM_T}
N 2690 -1240 2690 -1210 {
lab=IM_T}
N 2690 -1130 2730 -1130 {
lab=IM}
N 2690 -1130 2690 -1100 {
lab=IM}
N 2730 -1180 2730 -1130 {
lab=IM}
N 2730 -1210 2750 -1210 {
lab=VSS}
N 2750 -1210 2750 -1070 {
lab=VSS}
N 2730 -1070 2750 -1070 {
lab=VSS}
N 2730 -1100 2750 -1100 {
lab=VSS}
N 2620 -1360 2660 -1360 {
lab=C1}
C {MSB_UNIT_CELL.sym} 180 -1660 0 0 {name=x57}
C {MSB_UNIT_CELL.sym} 460 -1660 0 0 {name=x58}
C {MSB_UNIT_CELL.sym} 720 -1660 0 0 {name=x59}
C {MSB_UNIT_CELL.sym} 1000 -1660 0 0 {name=x60}
C {MSB_UNIT_CELL.sym} 1260 -1660 0 0 {name=x61}
C {MSB_UNIT_CELL.sym} 1540 -1660 0 0 {name=x62}
C {MSB_UNIT_CELL.sym} 1800 -1660 0 0 {name=x63}
C {MSB_UNIT_CELL.sym} 2080 -1660 0 0 {name=x64}
C {devices/lab_pin.sym} 200 -1780 0 0 {name=p1 sig_type=std_logic lab=IM}
C {devices/lab_pin.sym} 220 -1770 0 0 {name=p2 sig_type=std_logic lab=IM_T}
C {devices/lab_pin.sym} 240 -1760 0 0 {name=p3 sig_type=std_logic lab=VDD}
C {devices/lab_pin.sym} 320 -1750 0 0 {name=p4 sig_type=std_logic lab=IOUT+}
C {devices/lab_pin.sym} 330 -1740 0 0 {name=p5 sig_type=std_logic lab=IOUT-}
C {devices/lab_pin.sym} 220 -1600 0 0 {name=p6 sig_type=std_logic lab=VSS}
C {MSB_UNIT_CELL.sym} 180 -1440 0 0 {name=x1}
C {MSB_UNIT_CELL.sym} 460 -1440 0 0 {name=x2}
C {MSB_UNIT_CELL.sym} 720 -1440 0 0 {name=x3}
C {MSB_UNIT_CELL.sym} 1000 -1440 0 0 {name=x4}
C {MSB_UNIT_CELL.sym} 1260 -1440 0 0 {name=x5}
C {MSB_UNIT_CELL.sym} 1540 -1440 0 0 {name=x6}
C {MSB_UNIT_CELL.sym} 1800 -1440 0 0 {name=x7}
C {MSB_UNIT_CELL.sym} 2080 -1440 0 0 {name=x8}
C {devices/lab_pin.sym} 200 -1560 0 0 {name=p7 sig_type=std_logic lab=IM}
C {devices/lab_pin.sym} 220 -1550 0 0 {name=p8 sig_type=std_logic lab=IM_T}
C {devices/lab_pin.sym} 240 -1540 0 0 {name=p9 sig_type=std_logic lab=VDD}
C {devices/lab_pin.sym} 320 -1530 0 0 {name=p10 sig_type=std_logic lab=IOUT+}
C {devices/lab_pin.sym} 330 -1520 0 0 {name=p11 sig_type=std_logic lab=IOUT-}
C {devices/lab_pin.sym} 220 -1380 0 0 {name=p12 sig_type=std_logic lab=VSS}
C {MSB_UNIT_CELL.sym} 180 -1220 0 0 {name=x9}
C {MSB_UNIT_CELL.sym} 460 -1220 0 0 {name=x10}
C {MSB_UNIT_CELL.sym} 720 -1220 0 0 {name=x11}
C {MSB_UNIT_CELL.sym} 1000 -1220 0 0 {name=x12}
C {MSB_UNIT_CELL.sym} 1260 -1220 0 0 {name=x13}
C {MSB_UNIT_CELL.sym} 1540 -1220 0 0 {name=x14}
C {MSB_UNIT_CELL.sym} 1800 -1220 0 0 {name=x15}
C {MSB_UNIT_CELL.sym} 2080 -1220 0 0 {name=x16}
C {devices/lab_pin.sym} 200 -1340 0 0 {name=p13 sig_type=std_logic lab=IM}
C {devices/lab_pin.sym} 220 -1330 0 0 {name=p14 sig_type=std_logic lab=IM_T}
C {devices/lab_pin.sym} 240 -1320 0 0 {name=p15 sig_type=std_logic lab=VDD}
C {devices/lab_pin.sym} 320 -1310 0 0 {name=p16 sig_type=std_logic lab=IOUT+}
C {devices/lab_pin.sym} 330 -1300 0 0 {name=p17 sig_type=std_logic lab=IOUT-}
C {devices/lab_pin.sym} 220 -1160 0 0 {name=p18 sig_type=std_logic lab=VSS}
C {MSB_UNIT_CELL.sym} 180 -1000 0 0 {name=x17}
C {MSB_UNIT_CELL.sym} 460 -1000 0 0 {name=x18}
C {MSB_UNIT_CELL.sym} 720 -1000 0 0 {name=x19}
C {MSB_UNIT_CELL.sym} 1000 -1000 0 0 {name=x20}
C {MSB_UNIT_CELL.sym} 1260 -1000 0 0 {name=x21}
C {MSB_UNIT_CELL.sym} 1540 -1000 0 0 {name=x22}
C {MSB_UNIT_CELL.sym} 1800 -1000 0 0 {name=x23}
C {MSB_UNIT_CELL.sym} 2080 -1000 0 0 {name=x24}
C {devices/lab_pin.sym} 200 -1120 0 0 {name=p19 sig_type=std_logic lab=IM}
C {devices/lab_pin.sym} 220 -1110 0 0 {name=p20 sig_type=std_logic lab=IM_T}
C {devices/lab_pin.sym} 240 -1100 0 0 {name=p21 sig_type=std_logic lab=VDD}
C {devices/lab_pin.sym} 320 -1090 0 0 {name=p22 sig_type=std_logic lab=IOUT+}
C {devices/lab_pin.sym} 330 -1080 0 0 {name=p23 sig_type=std_logic lab=IOUT-}
C {devices/lab_pin.sym} 220 -940 0 0 {name=p24 sig_type=std_logic lab=VSS}
C {MSB_UNIT_CELL.sym} 180 -780 0 0 {name=x25}
C {MSB_UNIT_CELL.sym} 460 -780 0 0 {name=x26}
C {MSB_UNIT_CELL.sym} 720 -780 0 0 {name=x27}
C {MSB_UNIT_CELL.sym} 1000 -780 0 0 {name=x28}
C {MSB_UNIT_CELL.sym} 1260 -780 0 0 {name=x29}
C {MSB_UNIT_CELL.sym} 1540 -780 0 0 {name=x30}
C {MSB_UNIT_CELL.sym} 1800 -780 0 0 {name=x31}
C {MSB_UNIT_CELL.sym} 2080 -780 0 0 {name=x32}
C {devices/lab_pin.sym} 200 -900 0 0 {name=p25 sig_type=std_logic lab=IM}
C {devices/lab_pin.sym} 220 -890 0 0 {name=p26 sig_type=std_logic lab=IM_T}
C {devices/lab_pin.sym} 240 -880 0 0 {name=p27 sig_type=std_logic lab=VDD}
C {devices/lab_pin.sym} 320 -870 0 0 {name=p28 sig_type=std_logic lab=IOUT+}
C {devices/lab_pin.sym} 330 -860 0 0 {name=p29 sig_type=std_logic lab=IOUT-}
C {devices/lab_pin.sym} 220 -720 0 0 {name=p30 sig_type=std_logic lab=VSS}
C {MSB_UNIT_CELL.sym} 180 -560 0 0 {name=x33}
C {MSB_UNIT_CELL.sym} 460 -560 0 0 {name=x34}
C {MSB_UNIT_CELL.sym} 720 -560 0 0 {name=x35}
C {MSB_UNIT_CELL.sym} 1000 -560 0 0 {name=x36}
C {MSB_UNIT_CELL.sym} 1260 -560 0 0 {name=x37}
C {MSB_UNIT_CELL.sym} 1540 -560 0 0 {name=x38}
C {MSB_UNIT_CELL.sym} 1800 -560 0 0 {name=x39}
C {MSB_UNIT_CELL.sym} 2080 -560 0 0 {name=x40}
C {devices/lab_pin.sym} 200 -680 0 0 {name=p31 sig_type=std_logic lab=IM}
C {devices/lab_pin.sym} 220 -670 0 0 {name=p32 sig_type=std_logic lab=IM_T}
C {devices/lab_pin.sym} 240 -660 0 0 {name=p33 sig_type=std_logic lab=VDD}
C {devices/lab_pin.sym} 320 -650 0 0 {name=p34 sig_type=std_logic lab=IOUT+}
C {devices/lab_pin.sym} 330 -640 0 0 {name=p35 sig_type=std_logic lab=IOUT-}
C {devices/lab_pin.sym} 220 -500 0 0 {name=p36 sig_type=std_logic lab=VSS}
C {MSB_UNIT_CELL.sym} 180 -340 0 0 {name=x41}
C {MSB_UNIT_CELL.sym} 460 -340 0 0 {name=x42}
C {MSB_UNIT_CELL.sym} 720 -340 0 0 {name=x43}
C {MSB_UNIT_CELL.sym} 1000 -340 0 0 {name=x44}
C {MSB_UNIT_CELL.sym} 1260 -340 0 0 {name=x45}
C {MSB_UNIT_CELL.sym} 1540 -340 0 0 {name=x46}
C {MSB_UNIT_CELL.sym} 1800 -340 0 0 {name=x47}
C {MSB_UNIT_CELL.sym} 2080 -340 0 0 {name=x48}
C {devices/lab_pin.sym} 200 -460 0 0 {name=p37 sig_type=std_logic lab=IM}
C {devices/lab_pin.sym} 220 -450 0 0 {name=p38 sig_type=std_logic lab=IM_T}
C {devices/lab_pin.sym} 240 -440 0 0 {name=p39 sig_type=std_logic lab=VDD}
C {devices/lab_pin.sym} 320 -430 0 0 {name=p40 sig_type=std_logic lab=IOUT+}
C {devices/lab_pin.sym} 330 -420 0 0 {name=p41 sig_type=std_logic lab=IOUT-}
C {devices/lab_pin.sym} 220 -280 0 0 {name=p42 sig_type=std_logic lab=VSS}
C {MSB_UNIT_CELL.sym} 180 -120 0 0 {name=x49}
C {MSB_UNIT_CELL.sym} 460 -120 0 0 {name=x50}
C {MSB_UNIT_CELL.sym} 720 -120 0 0 {name=x51}
C {MSB_UNIT_CELL.sym} 1000 -120 0 0 {name=x52}
C {MSB_UNIT_CELL.sym} 1260 -120 0 0 {name=x53}
C {MSB_UNIT_CELL.sym} 1540 -120 0 0 {name=x54}
C {MSB_UNIT_CELL.sym} 1800 -120 0 0 {name=x55}
C {devices/lab_pin.sym} 200 -240 0 0 {name=p43 sig_type=std_logic lab=IM}
C {devices/lab_pin.sym} 220 -230 0 0 {name=p44 sig_type=std_logic lab=IM_T}
C {devices/lab_pin.sym} 240 -220 0 0 {name=p45 sig_type=std_logic lab=VDD}
C {devices/lab_pin.sym} 320 -210 0 0 {name=p46 sig_type=std_logic lab=IOUT+}
C {devices/lab_pin.sym} 330 -200 0 0 {name=p47 sig_type=std_logic lab=IOUT-}
C {devices/lab_pin.sym} 220 -60 0 0 {name=p48 sig_type=std_logic lab=VSS}
C {devices/lab_pin.sym} 100 -1690 0 0 {name=p49 sig_type=std_logic lab=VDD}
C {devices/lab_pin.sym} 110 -1670 0 0 {name=p50 sig_type=std_logic lab=R0}
C {devices/lab_pin.sym} 120 -1650 0 0 {name=p51 sig_type=std_logic lab=C0}
C {devices/lab_pin.sym} 100 -1470 0 0 {name=p52 sig_type=std_logic lab=R0}
C {devices/lab_pin.sym} 390 -1650 0 0 {name=p53 sig_type=std_logic lab=C1}
C {devices/lab_pin.sym} 650 -1650 0 0 {name=p54 sig_type=std_logic lab=C2}
C {devices/lab_pin.sym} 920 -1650 0 0 {name=p55 sig_type=std_logic lab=C3}
C {devices/lab_pin.sym} 1190 -1650 0 0 {name=p56 sig_type=std_logic lab=C4}
C {devices/lab_pin.sym} 1460 -1650 0 0 {name=p57 sig_type=std_logic lab=C5}
C {devices/lab_pin.sym} 1730 -1650 0 0 {name=p58 sig_type=std_logic lab=C6}
C {devices/lab_pin.sym} 2010 -1650 0 0 {name=p59 sig_type=std_logic lab=VSS}
C {devices/lab_pin.sym} 110 -1450 0 0 {name=p60 sig_type=std_logic lab=R1}
C {devices/lab_pin.sym} 100 -1250 0 0 {name=p61 sig_type=std_logic lab=R1}
C {devices/lab_pin.sym} 110 -1230 0 0 {name=p62 sig_type=std_logic lab=R2}
C {devices/lab_pin.sym} 100 -1030 0 0 {name=p63 sig_type=std_logic lab=R2}
C {devices/lab_pin.sym} 110 -1010 0 0 {name=p64 sig_type=std_logic lab=R3}
C {devices/lab_pin.sym} 100 -810 0 0 {name=p65 sig_type=std_logic lab=R3}
C {devices/lab_pin.sym} 110 -790 0 0 {name=p66 sig_type=std_logic lab=R4}
C {devices/lab_pin.sym} 100 -590 0 0 {name=p67 sig_type=std_logic lab=R4}
C {devices/lab_pin.sym} 110 -570 0 0 {name=p68 sig_type=std_logic lab=R5}
C {devices/lab_pin.sym} 100 -370 0 0 {name=p69 sig_type=std_logic lab=R5}
C {devices/lab_pin.sym} 110 -350 0 0 {name=p70 sig_type=std_logic lab=R6}
C {devices/lab_pin.sym} 100 -150 0 0 {name=p71 sig_type=std_logic lab=R6}
C {devices/lab_pin.sym} 110 -130 0 0 {name=p72 sig_type=std_logic lab=VSS}
C {Thermo_Decoder.sym} 2480 -1380 0 0 {name=x56}
C {Thermo_Decoder.sym} 2870 -1380 0 0 {name=x65}
C {devices/lab_pin.sym} 2670 -1490 0 0 {name=p73 sig_type=std_logic lab=VDD}
C {devices/lab_pin.sym} 2690 -1310 0 0 {name=p74 sig_type=std_logic lab=VSS}
C {devices/lab_pin.sym} 2660 -1460 0 0 {name=p76 sig_type=std_logic lab=C6}
C {devices/lab_pin.sym} 2660 -1440 0 0 {name=p78 sig_type=std_logic lab=C5}
C {devices/lab_pin.sym} 2660 -1420 0 0 {name=p80 sig_type=std_logic lab=C4}
C {devices/lab_pin.sym} 2660 -1400 0 0 {name=p82 sig_type=std_logic lab=C3}
C {devices/lab_pin.sym} 2660 -1380 0 0 {name=p84 sig_type=std_logic lab=C2}
C {devices/lab_pin.sym} 2660 -1360 0 0 {name=p86 sig_type=std_logic lab=C1}
C {devices/lab_pin.sym} 2660 -1340 0 0 {name=p88 sig_type=std_logic lab=C0}
C {devices/lab_pin.sym} 3050 -1460 0 0 {name=p79 sig_type=std_logic lab=R6}
C {devices/lab_pin.sym} 3050 -1440 0 0 {name=p81 sig_type=std_logic lab=R5}
C {devices/lab_pin.sym} 3050 -1420 0 0 {name=p83 sig_type=std_logic lab=R4}
C {devices/lab_pin.sym} 3050 -1400 0 0 {name=p85 sig_type=std_logic lab=R3}
C {devices/lab_pin.sym} 3050 -1380 0 0 {name=p87 sig_type=std_logic lab=R2}
C {devices/lab_pin.sym} 3050 -1360 0 0 {name=p89 sig_type=std_logic lab=R1}
C {devices/lab_pin.sym} 3050 -1340 0 0 {name=p90 sig_type=std_logic lab=R0}
C {devices/lab_pin.sym} 2350 -1420 0 0 {name=p91 sig_type=std_logic lab=B9}
C {devices/lab_pin.sym} 2350 -1400 0 0 {name=p92 sig_type=std_logic lab=B8}
C {devices/lab_pin.sym} 2350 -1380 0 0 {name=p93 sig_type=std_logic lab=B7}
C {devices/lab_pin.sym} 2740 -1420 0 0 {name=p94 sig_type=std_logic lab=B12}
C {devices/lab_pin.sym} 2740 -1400 0 0 {name=p95 sig_type=std_logic lab=B11}
C {devices/lab_pin.sym} 2740 -1380 0 0 {name=p96 sig_type=std_logic lab=B10}
C {devices/iopin.sym} 2360 -1240 0 0 {name=p97 lab=VDD}
C {devices/iopin.sym} 2450 -1240 0 0 {name=p98 lab=VSS}
C {devices/ipin.sym} 2410 -1200 0 0 {name=p99 lab=B7}
C {devices/ipin.sym} 2500 -1200 0 0 {name=p100 lab=B11}
C {devices/ipin.sym} 2410 -1170 0 0 {name=p101 lab=B8}
C {devices/ipin.sym} 2500 -1170 0 0 {name=p102 lab=B12}
C {devices/ipin.sym} 2410 -1140 0 0 {name=p103 lab=B9}
C {devices/ipin.sym} 2500 -1140 0 0 {name=p104 lab=IM_T}
C {devices/ipin.sym} 2410 -1110 0 0 {name=p105 lab=B10}
C {devices/opin.sym} 2360 -1070 0 0 {name=p106 lab=IOUT+}
C {devices/opin.sym} 2450 -1070 0 0 {name=p107 lab=IOUT-}
C {symbols/nfet_03v3.sym} 2710 -1210 0 0 {name=M1
L=0.5u
W=0.6u
nf=1
m=1
ad="'int((nf+1)/2) * W/nf * 0.18u'"
pd="'2*int((nf+1)/2) * (W/nf + 0.18u)'"
as="'int((nf+2)/2) * W/nf * 0.18u'"
ps="'2*int((nf+2)/2) * (W/nf + 0.18u)'"
nrd="'0.18u / W'" nrs="'0.18u / W'"
sa=0 sb=0 sd=0
model=nfet_03v3
spiceprefix=X
}
C {symbols/nfet_03v3.sym} 2710 -1100 0 0 {name=M2
L=0.5u
W=0.6u
nf=1
m=1
ad="'int((nf+1)/2) * W/nf * 0.18u'"
pd="'2*int((nf+1)/2) * (W/nf + 0.18u)'"
as="'int((nf+2)/2) * W/nf * 0.18u'"
ps="'2*int((nf+2)/2) * (W/nf + 0.18u)'"
nrd="'0.18u / W'" nrs="'0.18u / W'"
sa=0 sb=0 sd=0
model=nfet_03v3
spiceprefix=X
}
C {devices/lab_pin.sym} 2750 -1160 0 0 {name=p108 sig_type=std_logic lab=VSS}
C {devices/lab_pin.sym} 2690 -1240 0 0 {name=p109 sig_type=std_logic lab=IM_T}
C {devices/lab_pin.sym} 2690 -1130 0 0 {name=p110 sig_type=std_logic lab=IM}
